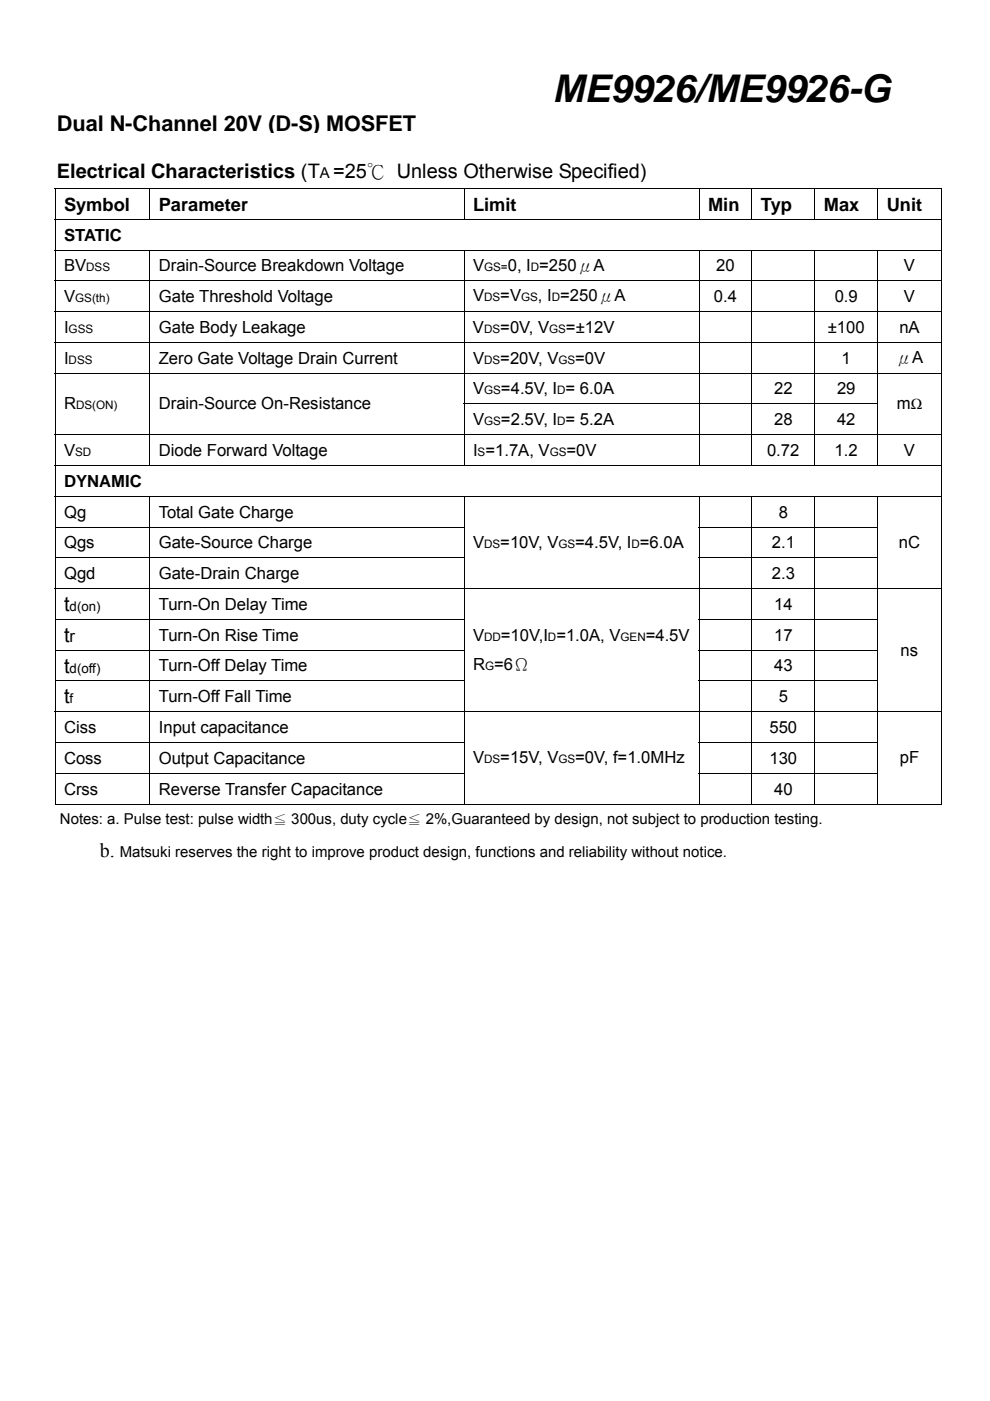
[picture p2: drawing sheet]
<svg xmlns="http://www.w3.org/2000/svg" width="210mm" height="297mm" viewBox="0 0 210 297" stroke-linecap="round" stroke-linejoin="round" font-family="sans-serif">
<defs><g id="words">
<text font-size="8.1" x="117.2" y="21.6">ME9926/ME9926-G</text>
<text font-size="4.6" x="12.1" y="27.8">Dual N-Channel 20V (D-S) MOSFET</text>
<g font-size="4.2">
<text x="12.1" y="37.7">Electrical Characteristics (T =25℃ Unless Otherwise Specified)</text>
<text x="13.6" y="129.6">t</text>
<text x="13.6" y="136.1">t</text>
<text x="13.6" y="142.6">t</text>
<text x="13.6" y="149.1">t</text>
<text x="21.2" y="181.6">b.</text>
</g>
<g font-size="3.9">
<text x="13.6" y="44.7">Symbol</text>
<text x="33.7" y="44.7">Parameter</text>
<text x="100.3" y="44.7">Limit</text>
<text x="150.2" y="44.7">Min</text>
<text x="161.4" y="44.7">Typ</text>
<text x="174.7" y="44.7">Max</text>
<text x="188.1" y="44.7">Unit</text>
</g>
<g font-size="3.5">
<text x="13.6" y="51.1">STATIC</text>
<text x="13.6" y="57.5">BV</text>
<text x="33.7" y="57.5">Drain-Source Breakdown Voltage</text>
<text x="100.3" y="57.4">V</text>
<text x="107.7" y="57.4">0, I =250μA</text>
<text x="151.9" y="57.5">20</text>
<text x="191.7" y="57.5">V</text>
<text x="13.6" y="64.1">V</text>
<text x="33.7" y="64.1">Gate Threshold Voltage</text>
<text x="100.3" y="63.9">V</text>
<text x="106.1" y="63.9">=V</text>
<text x="114.1" y="63.9">, I =250μA</text>
<text x="151.4" y="64.1">0.4</text>
<text x="177" y="64.1">0.9</text>
<text x="191.7" y="64.1">V</text>
<text x="13.6" y="70.6">I</text>
<text x="33.7" y="70.6">Gate Body Leakage</text>
<text x="100.3" y="70.6">V</text>
<text x="106.1" y="70.6">=0V, V</text>
<text x="120" y="70.6">=±12V</text>
<text x="175.6" y="70.6">±100</text>
<text x="190.8" y="70.6">nA</text>
<text x="13.6" y="77.1">I</text>
<text x="33.7" y="77.1">Zero Gate Voltage Drain Current</text>
<text x="100.3" y="77.1">V</text>
<text x="106.1" y="77.1">=20V, V</text>
<text x="122" y="77.1">=0V</text>
<text x="178.5" y="77.1">1</text>
<text x="190" y="76.9">μA</text>
<text x="100.3" y="83.6">V</text>
<text x="106.3" y="83.6">=4.5V, I = 6.0A</text>
<text x="164.2" y="83.6">22</text>
<text x="177.5" y="83.6">29</text>
<text x="13.6" y="86.8">R</text>
<text x="33.7" y="86.8">Drain-Source On-Resistance</text>
<text x="190.2" y="86.8">mΩ</text>
<text x="100.3" y="90.1">V</text>
<text x="106.3" y="90.1">=2.5V, I = 5.2A</text>
<text x="164.2" y="90.1">28</text>
<text x="177.5" y="90.1">42</text>
<text x="13.6" y="96.7">V</text>
<text x="33.7" y="96.7">Diode Forward Voltage</text>
<text x="100.3" y="96.7">I =1.7A, V</text>
<text x="120.2" y="96.7">=0V</text>
<text x="162.7" y="96.7">0.72</text>
<text x="177" y="96.7">1.2</text>
<text x="191.7" y="96.7">V</text>
<text x="13.6" y="103.3">DYNAMIC</text>
<text x="13.6" y="109.7">Qg</text>
<text x="33.7" y="109.7">Total Gate Charge</text>
<text x="165.2" y="109.7">8</text>
<text x="13.6" y="116.3">Qgs</text>
<text x="33.7" y="116.3">Gate-Source Charge</text>
<text x="100.3" y="116.2">V</text>
<text x="106.1" y="116.2">=10V, V</text>
<text x="122" y="116.2">=4.5V, I =6.0A</text>
<text x="163.7" y="116.3">2.1</text>
<text x="190.6" y="116.2">nC</text>
<text x="13.6" y="122.8">Qgd</text>
<text x="33.7" y="122.8">Gate-Drain Charge</text>
<text x="163.7" y="122.8">2.3</text>
<text x="33.7" y="129.3">Turn-On Delay Time</text>
<text x="164.2" y="129.3">14</text>
<text x="14.8" y="136.1">r</text>
<text x="33.7" y="135.8">Turn-On Rise Time</text>
<text x="100.3" y="135.8">V</text>
<text x="106.2" y="135.8">=10V,I =1.0A, V</text>
<text x="137" y="135.8">=4.5V</text>
<text x="164.2" y="135.8">17</text>
<text x="33.7" y="142.4">Turn-Off Delay Time</text>
<text x="100.3" y="142">R =6Ω</text>
<text x="164.2" y="142.4">43</text>
<text x="191" y="139">ns</text>
<text x="33.7" y="148.9">Turn-Off Fall Time</text>
<text x="165.2" y="148.9">5</text>
<text x="13.6" y="155.4">Ciss</text>
<text x="33.7" y="155.4">Input capacitance</text>
<text x="163.2" y="155.4">550</text>
<text x="13.6" y="161.9">Coss</text>
<text x="33.7" y="161.9">Output Capacitance</text>
<text x="100.3" y="161.9">V</text>
<text x="106.1" y="161.9">=15V, V</text>
<text x="122" y="161.9">=0V, f=1.0MHz</text>
<text x="163.2" y="161.9">130</text>
<text x="190.8" y="161.9">pF</text>
<text x="13.6" y="168.5">Crss</text>
<text x="33.7" y="168.5">Reverse Transfer Capacitance</text>
<text x="164.2" y="168.5">40</text>
</g>
<g font-size="3.2">
<text x="67.8" y="37.7">A</text>
<text x="12.7" y="174.7">Notes: a. Pulse test: pulse width≦ 300us, duty cycle≦ 2%,Guaranteed by design, not subject to production testing.</text>
<text x="25.4" y="181.6">Matsuki reserves the right to improve product design, functions and reliability without notice.</text>
</g>
<g font-size="2.8">
<text x="14.8" y="129.6">d(on)</text>
<text x="14.8" y="142.6">d(off)</text>
<text x="14.8" y="149.1">f</text>
</g>
<g font-size="2.5">
<text x="18.3" y="57.5">DSS</text>
<text x="102.7" y="57.4">GS=</text>
<text x="112.6" y="57.4">D</text>
<text x="15.9" y="64.1">GS(th)</text>
<text x="102.7" y="63.9">DS</text>
<text x="110.5" y="63.9">GS</text>
<text x="117" y="63.9">D</text>
<text x="14.6" y="70.6">GSS</text>
<text x="102.7" y="70.6">DS</text>
<text x="116.5" y="70.6">GS</text>
<text x="14.6" y="77.1">DSS</text>
<text x="102.7" y="77.1">DS</text>
<text x="118.4" y="77.1">GS</text>
<text x="102.7" y="83.6">GS</text>
<text x="118.2" y="83.6">D</text>
<text x="16.2" y="86.8">DS(ON)</text>
<text x="102.7" y="90.1">GS</text>
<text x="118.2" y="90.1">D</text>
<text x="15.9" y="96.7">SD</text>
<text x="101.3" y="96.7">S</text>
<text x="116.6" y="96.7">GS</text>
<text x="102.7" y="116.2">DS</text>
<text x="118.4" y="116.2">GS</text>
<text x="133.9" y="116.2">D</text>
<text x="102.7" y="135.8">DD</text>
<text x="116.2" y="135.8">D</text>
<text x="131.6" y="135.8">GEN</text>
<text x="102.9" y="142">G</text>
<text x="102.7" y="161.9">DS</text>
<text x="118.4" y="161.9">GS</text>
</g>
</g></defs>
<g fill="#000">
<path d="M11.6 39.9h.2v.1h-.2zM199.6 39.9h.1v.1h-.1zM11.6 85.6h.2v.1h-.2zM31.7 85.6h.2v.1h-.2zM199.6 85.6h.1v.1h-.1zM199.6 111.7h.1v.1h-.1zM199.6 118.2h.1v.2h-.1zM199.6 131.3h.1v.1h-.1zM199.6 137.8h.1v.1h-.1zM199.6 144.3h.1v.2h-.1zM199.6 157.4h.1v.1h-.1zM199.6 163.9h.1v.1h-.1z"/>
<path d="M199.6 170.4h.1v.2h-.1z"/>
</g>
<g fill="none" stroke="#000" stroke-width=".21">
<path d="M11.6 40h188.1M11.6 46.5h188.1M11.6 53h188.1M11.6 59.5h188.1M11.7 40v6.4M11.7 46.6v6.3M11.7 53.1v6.4M11.7 59.6v6.4M31.8 40v6.4M31.8 53.1v6.4M31.8 59.6v6.4M98.4 40v6.4"/>
<path d="M98.4 53.1v6.4M98.4 59.6v6.4M148.3 40v6.4M148.3 53.1v6.4M148.3 59.6v6.4M159.5 40v6.4M159.5 53.1v6.4M159.5 59.6v6.4M172.8 40v6.4M172.8 53.1v6.4M172.8 59.6v6.4M186.2 40v6.4"/>
<path d="M186.2 53.1v6.4M186.2 59.6v6.4M199.7 40v6.4M199.7 46.6v6.3M199.7 53.1v6.4M199.7 59.6v6.4M11.6 66.1h188.1M11.6 72.6h188.1M11.6 79.1h188.1M11.7 66.1v6.4M11.7 72.7v6.3M11.7 79.2v6.4"/>
<path d="M31.8 66.1v6.4M31.8 72.7v6.3M31.8 79.2v6.4M98.4 66.1v6.4M98.4 72.7v6.3M98.4 79.2v6.4M148.3 66.1v6.4M148.3 72.7v6.3M148.3 79.2v6.4M159.5 66.1v6.4M159.5 72.7v6.3M159.5 79.2v6.4"/>
<path d="M172.8 66.1v6.4M172.8 72.7v6.3M172.8 79.2v6.4M186.2 66.1v6.4M186.2 72.7v6.3M186.2 79.2v6.4M199.7 66.1v6.4M199.7 72.7v6.3M199.7 79.2v6.4M11.6 92.2h188.1M11.6 98.7h188.1M11.7 85.7v6.4"/>
<path d="M11.7 92.3v6.3M11.7 98.8v6.3M31.8 85.7v6.4M31.8 92.3v6.3M98.3 85.6h87.9M98.4 85.7v6.4M98.4 92.3v6.3M148.3 85.7v6.4M148.3 92.3v6.3M159.5 85.7v6.4M159.5 92.3v6.3M172.8 85.7v6.4"/>
<path d="M172.8 92.3v6.3M186.2 85.7v6.4M186.2 92.3v6.3M199.7 85.7v6.4M199.7 92.3v6.3M199.7 98.8v6.3M11.6 105.2h188.1M11.6 111.8h86.9M11.6 118.3h86.9M11.7 105.3v6.4M11.7 111.8v6.4M11.7 118.4v6.3"/>
<path d="M31.8 105.3v6.4M31.8 111.8v6.4M31.8 118.4v6.3M98.4 105.3v6.4M98.4 111.8v6.4M98.4 118.4v6.3M148.2 111.8h38M148.2 118.3h38M148.3 105.3v6.4M148.3 111.8v6.4M148.3 118.4v6.3M159.5 105.3v6.4"/>
<path d="M159.5 111.8v6.4M159.5 118.4v6.3M172.8 105.3v6.4M172.8 111.8v6.4M172.8 118.4v6.3M186.2 105.3v6.4M186.2 111.8v6.4M186.2 118.4v6.3M199.7 105.3v6.4M199.7 111.8v6.4M199.7 118.4v6.3M11.6 124.8h188.1"/>
<path d="M11.6 131.3h86.9M11.6 137.9h86.9M11.7 124.9v6.4M11.7 131.4v6.4M11.7 137.9v6.4M31.8 124.9v6.4M31.8 131.4v6.4M31.8 137.9v6.4M98.4 124.9v6.4M98.4 131.4v6.4M98.4 137.9v6.4M148.2 131.3h38"/>
<path d="M148.2 137.9h38M148.3 124.9v6.4M148.3 131.4v6.4M148.3 137.9v6.4M159.5 124.9v6.4M159.5 131.4v6.4M159.5 137.9v6.4M172.8 124.9v6.4M172.8 131.4v6.4M172.8 137.9v6.4M186.2 124.9v6.4M186.2 131.4v6.4"/>
<path d="M186.2 137.9v6.4M199.7 124.9v6.4M199.7 131.4v6.4M199.7 137.9v6.4M11.6 144.4h86.9M11.6 150.9h188.1M11.6 157.4h86.9M11.7 144.5v6.3M11.7 151v6.4M11.7 157.5v6.4M31.8 144.5v6.3M31.8 151v6.4"/>
<path d="M31.8 157.5v6.4M98.4 144.5v6.3M98.4 151v6.4M98.4 157.5v6.4M148.2 144.4h38M148.2 157.4h38M148.3 144.5v6.3M148.3 151v6.4M148.3 157.5v6.4M159.5 144.5v6.3M159.5 151v6.4M159.5 157.5v6.4"/>
<path d="M172.8 144.5v6.3M172.8 151v6.4M172.8 157.5v6.4M186.2 144.5v6.3M186.2 151v6.4M186.2 157.5v6.4M199.7 144.5v6.3M199.7 151v6.4M199.7 157.5v6.4M11.6 164h86.9M11.6 170.5h20.1M11.7 164v6.6"/>
<path d="M31.8 164v6.6M31.9 170.5h66.4M98.4 164v6.6M98.5 170.5h49.7M148.2 164h38M148.3 164v6.6M148.4 170.5h11M159.5 164v6.6M159.6 170.5h13.1M172.8 164v6.6M172.9 170.5h13.2M186.2 164v6.6"/>
<path d="M186.2 170.5h13.4M199.7 164v6.6"/>
</g>
<use href="#words"/>
</svg>
